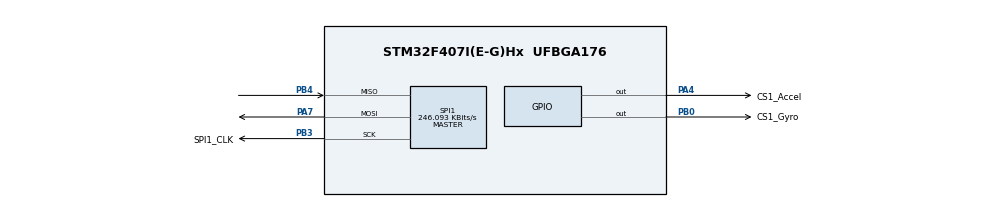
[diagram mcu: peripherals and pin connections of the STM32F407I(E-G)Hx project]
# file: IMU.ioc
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Mcu.Family=STM32F4
Mcu.Name=STM32F407I(E-G)Hx
Mcu.Package=UFBGA176
NVIC.PriorityGroup=NVIC_PRIORITYGROUP_4
PA13.Mode=Serial_Wire
PA13.Signal=SYS_JTMS-SWDIO
PA14.Mode=Serial_Wire
PA14.Signal=SYS_JTCK-SWCLK
PA4.GPIO_Label=CS1_Accel
PA4.PinState=GPIO_PIN_SET
PA4.Signal=GPIO_Output
PA7.Mode=Full_Duplex_Master
PA7.Signal=SPI1_MOSI
PB0.GPIO_Label=CS1_Gyro
PB0.PinState=GPIO_PIN_SET
PB0.Signal=GPIO_Output
PB3.GPIO_Label=SPI1_CLK
PB3.Mode=Full_Duplex_Master
PB3.Signal=SPI1_SCK
PB4.Mode=Full_Duplex_Master
PB4.Signal=SPI1_MISO
PH0-OSC_IN.Mode=HSE-External-Oscillator
PH0-OSC_IN.Signal=RCC_OSC_IN
PH1-OSC_OUT.Mode=HSE-External-Oscillator
PH1-OSC_OUT.Signal=RCC_OSC_OUT
ProjectManager.HeapSize=0x200
ProjectManager.StackSize=0x400
ProjectManager.TargetToolchain=MDK-ARM V5.32
RCC.48MHZClocksFreq_Value=63000000
RCC.AHBFreq_Value=126000000
RCC.APB1CLKDivider=RCC_HCLK_DIV4
RCC.APB1Freq_Value=31500000
RCC.APB1TimFreq_Value=63000000
RCC.APB2CLKDivider=RCC_HCLK_DIV2
RCC.APB2Freq_Value=63000000
RCC.APB2TimFreq_Value=126000000
RCC.CortexFreq_Value=126000000
RCC.HCLKFreq_Value=126000000
RCC.HSE_VALUE=12000000
RCC.HSI_VALUE=16000000
RCC.LSE_VALUE=32768
RCC.PLLM=8
RCC.PLLN=168
RCC.PLLSourceVirtual=RCC_PLLSOURCE_HSE
RCC.SYSCLKFreq_VALUE=126000000
RCC.SYSCLKSource=RCC_SYSCLKSOURCE_PLLCLK
RCC.VCOOutputFreq_Value=252000000
SPI1.BaudRatePrescaler=SPI_BAUDRATEPRESCALER_256
SPI1.CLKPhase=SPI_PHASE_2EDGE
SPI1.CLKPolarity=SPI_POLARITY_HIGH
SPI1.CalculateBaudRate=246.093 KBits/s
SPI1.Direction=SPI_DIRECTION_2LINES
SPI1.Mode=SPI_MODE_MASTER
SPI1.VirtualType=VM_MASTER
board=custom

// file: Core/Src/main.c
/* USER CODE BEGIN Header */
/**
  ******************************************************************************
  * @file           : main.c
  * @brief          : Main program body
  ******************************************************************************
  * @attention
  *
  * Copyright (c) 2024 STMicroelectronics.
  * All rights reserved.
  *
  * This software is licensed under terms that can be found in the LICENSE file
  * in the root directory of this software component.
  * If no LICENSE file comes with this software, it is provided AS-IS.
  *
  ******************************************************************************
  */
/* USER CODE END Header */
#include "main.h"
#include "spi.h"
#include "gpio.h"

void SystemClock_Config(void);

int main(void)
{

  /* MCU Configuration--------------------------------------------------------*/

  /* Reset of all peripherals, Initializes the Flash interface and the Systick. */
  HAL_Init();

  /* Configure the system clock */
  SystemClock_Config();

  /* Initialize all configured peripherals */
  MX_GPIO_Init();
  MX_SPI1_Init();

  /* Infinite loop */
  while (1)
  {

  }
}

void SystemClock_Config(void)
{
  RCC_OscInitTypeDef RCC_OscInitStruct = {0};
  RCC_ClkInitTypeDef RCC_ClkInitStruct = {0};

  /** Configure the main internal regulator output voltage
  */
  __HAL_RCC_PWR_CLK_ENABLE();
  __HAL_PWR_VOLTAGESCALING_CONFIG(PWR_REGULATOR_VOLTAGE_SCALE1);

  /** Initializes the RCC Oscillators according to the specified parameters
  * in the RCC_OscInitTypeDef structure.
  */
  RCC_OscInitStruct.OscillatorType = RCC_OSCILLATORTYPE_HSI;
  RCC_OscInitStruct.HSIState = RCC_HSI_ON;
  RCC_OscInitStruct.HSICalibrationValue = RCC_HSICALIBRATION_DEFAULT;
  RCC_OscInitStruct.PLL.PLLState = RCC_PLL_ON;
  RCC_OscInitStruct.PLL.PLLSource = RCC_PLLSOURCE_HSI;
  RCC_OscInitStruct.PLL.PLLM = 8;
  RCC_OscInitStruct.PLL.PLLN = 168;
  RCC_OscInitStruct.PLL.PLLP = RCC_PLLP_DIV2;
  RCC_OscInitStruct.PLL.PLLQ = 4;
  if (HAL_RCC_OscConfig(&RCC_OscInitStruct) != HAL_OK)
  {
    Error_Handler();
  }

  /** Initializes the CPU, AHB and APB buses clocks
  */
  RCC_ClkInitStruct.ClockType = RCC_CLOCKTYPE_HCLK|RCC_CLOCKTYPE_SYSCLK
                              |RCC_CLOCKTYPE_PCLK1|RCC_CLOCKTYPE_PCLK2;
  RCC_ClkInitStruct.SYSCLKSource = RCC_SYSCLKSOURCE_PLLCLK;
  RCC_ClkInitStruct.AHBCLKDivider = RCC_SYSCLK_DIV1;
  RCC_ClkInitStruct.APB1CLKDivider = RCC_HCLK_DIV4;
  RCC_ClkInitStruct.APB2CLKDivider = RCC_HCLK_DIV2;

  if (HAL_RCC_ClockConfig(&RCC_ClkInitStruct, FLASH_LATENCY_5) != HAL_OK)
  {
    Error_Handler();
  }
}

void Error_Handler(void)
{
  __disable_irq();
  while (1)
  {
  }
}
